VERSION 5.8 ;
BUSBITCHARS "[]" ;
DIVIDERCHAR "/" ;
CLEARANCEMEASURE EUCLIDEAN ;

SITE coresite_DH_P
    SIZE 0.0450 BY 0.2880 ;
    CLASS CORE ;
    SYMMETRY X Y ;
END coresite_DH_P

SITE coresite_DH_N
    SIZE 0.0450 BY 0.2880 ;
    CLASS CORE ;
    SYMMETRY X Y ;
END coresite_DH_N

SITE coresite
    SIZE 0.0450 BY 0.1440 ;
    CLASS CORE ;
    SYMMETRY X Y ;
END coresite

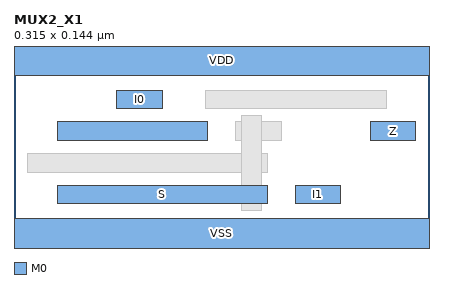
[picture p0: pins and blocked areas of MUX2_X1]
MACRO MUX2_X1
  CLASS CORE ;
  ORIGIN 0 0 ;
  FOREIGN MUX2_X1 0 0 ;
  SIZE 0.3150 BY 0.1440 ;
  SYMMETRY X Y ;
  SITE coresite ;
  PIN S
    DIRECTION INPUT ;
    USE SIGNAL ;
    PORT
      LAYER M0 ;
        RECT 0.0330 0.0430 0.1920 0.0290 ;
        RECT 0.0330 0.0910 0.1470 0.0770 ;
    END
  END S
  PIN I1
    DIRECTION INPUT ;
    USE SIGNAL ;
    PORT
      LAYER M0 ;
        RECT 0.2130 0.0430 0.2475 0.0290 ;
    END
  END I1
  PIN Z
    DIRECTION OUTPUT ;
    USE SIGNAL ;
    PORT
      LAYER M0 ;
        RECT 0.2700 0.0910 0.3045 0.0770 ;
    END
  END Z
  PIN I0
    DIRECTION INPUT ;
    USE SIGNAL ;
    PORT
      LAYER M0 ;
        RECT 0.0780 0.1150 0.1125 0.1010 ;
    END
  END I0
  PIN VDD
    DIRECTION INOUT ;
    USE POWER ;
    SHAPE ABUTMENT ;
    PORT
      LAYER M0 ;
        RECT 0.0000 0.1260 0.3150 0.1620 ;
    END
  END VDD
  PIN VSS
    DIRECTION INOUT ;
    USE GROUND ;
    SHAPE ABUTMENT ;
    PORT
      LAYER M0 ;
        RECT 0.0000 -0.0180 0.3150 0.0180 ;
    END
  END VSS
  OBS
      LAYER V0 ;
        RECT 0.1730 0.0770 0.1870 0.0910 ;
        RECT 0.1730 0.0530 0.1870 0.0670 ;
      LAYER M0 ;
        RECT 0.0105 0.0530 0.1920 0.0670 ;
        RECT 0.1680 0.0770 0.2025 0.0910 ;
        RECT 0.1455 0.1010 0.2820 0.1150 ;
      LAYER M1 ;
        RECT 0.1725 0.0960 0.1875 0.0240 ;
  END
END MUX2_X1

END LIBRARY
